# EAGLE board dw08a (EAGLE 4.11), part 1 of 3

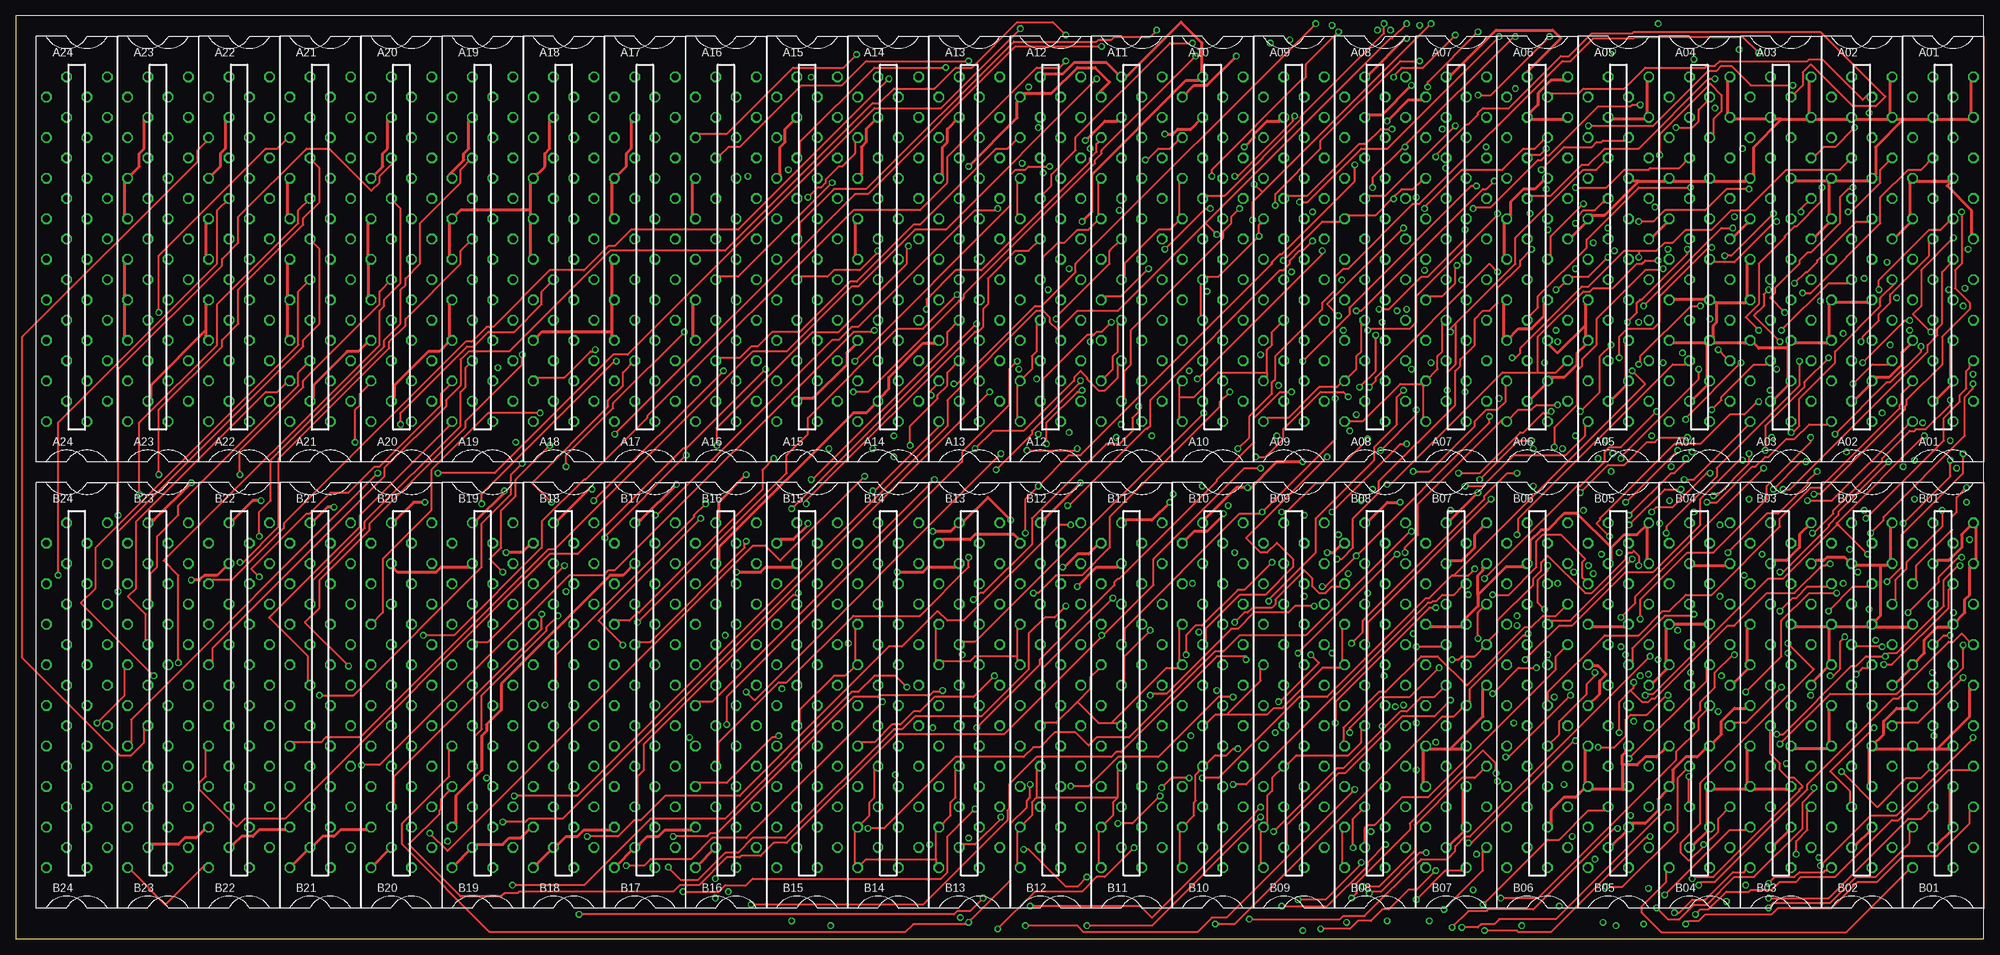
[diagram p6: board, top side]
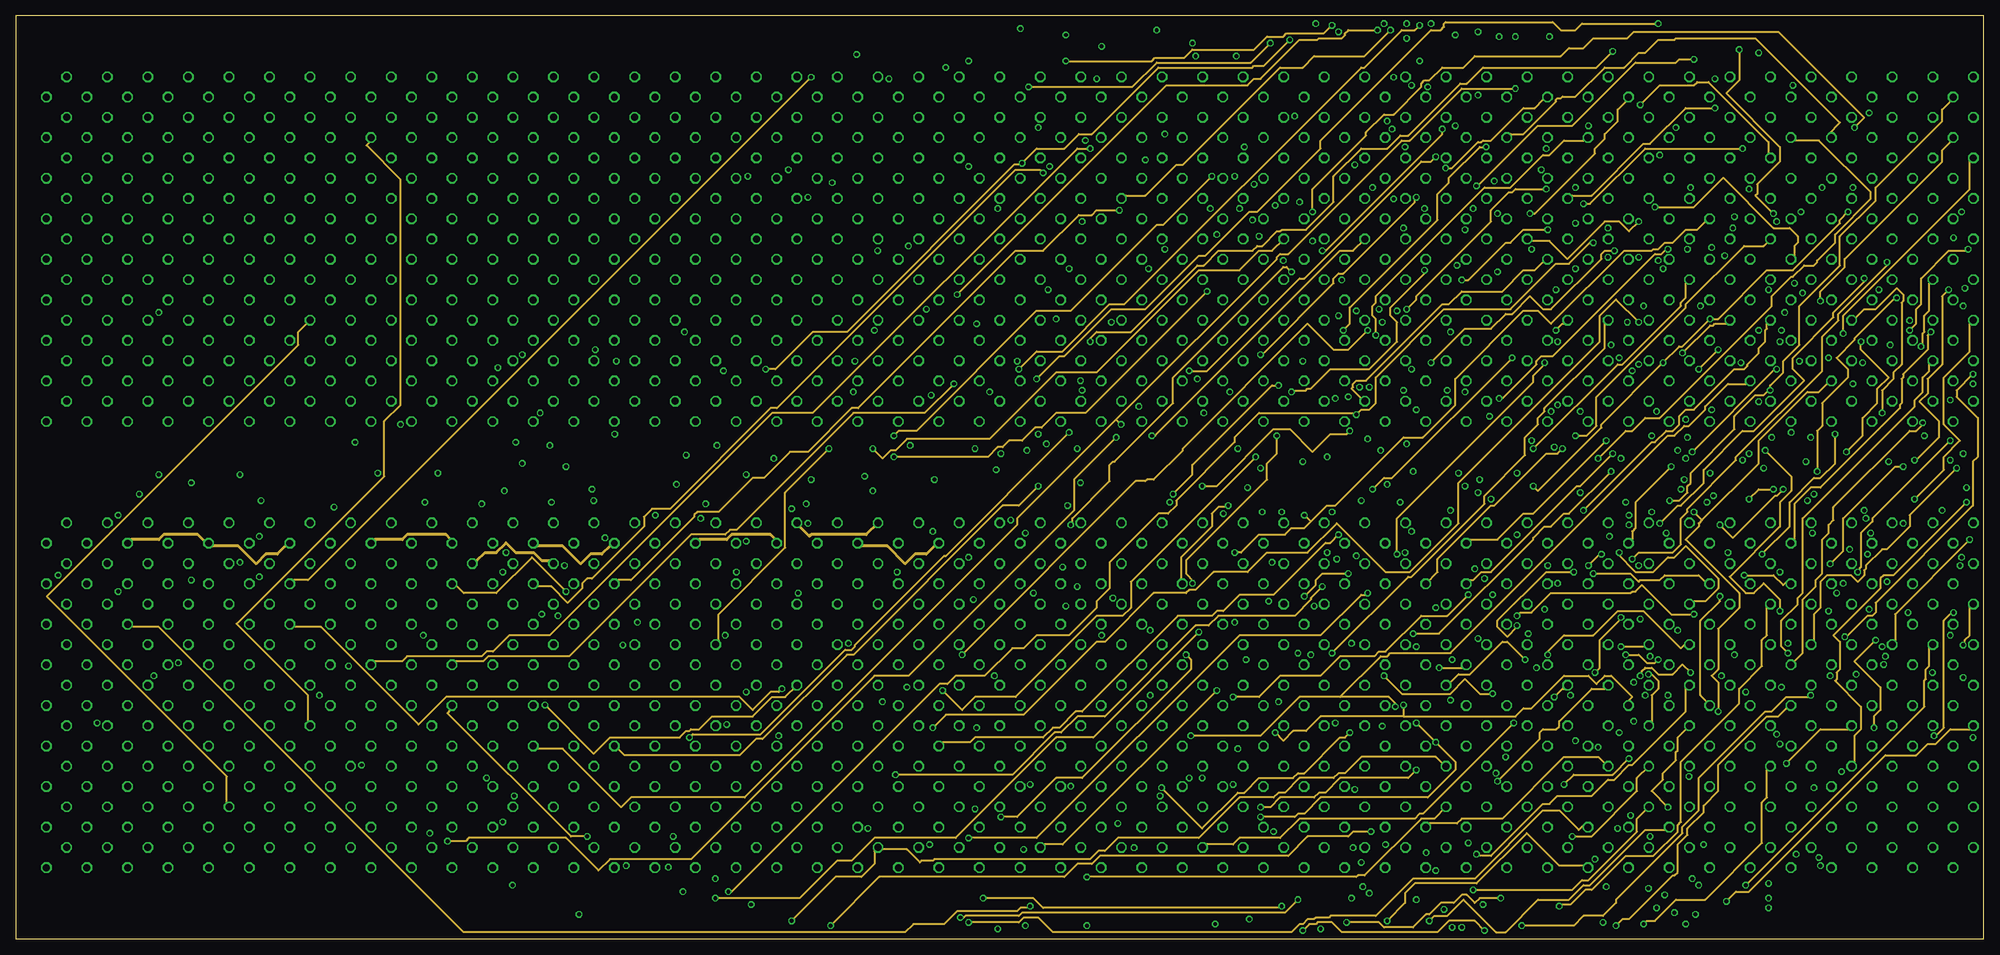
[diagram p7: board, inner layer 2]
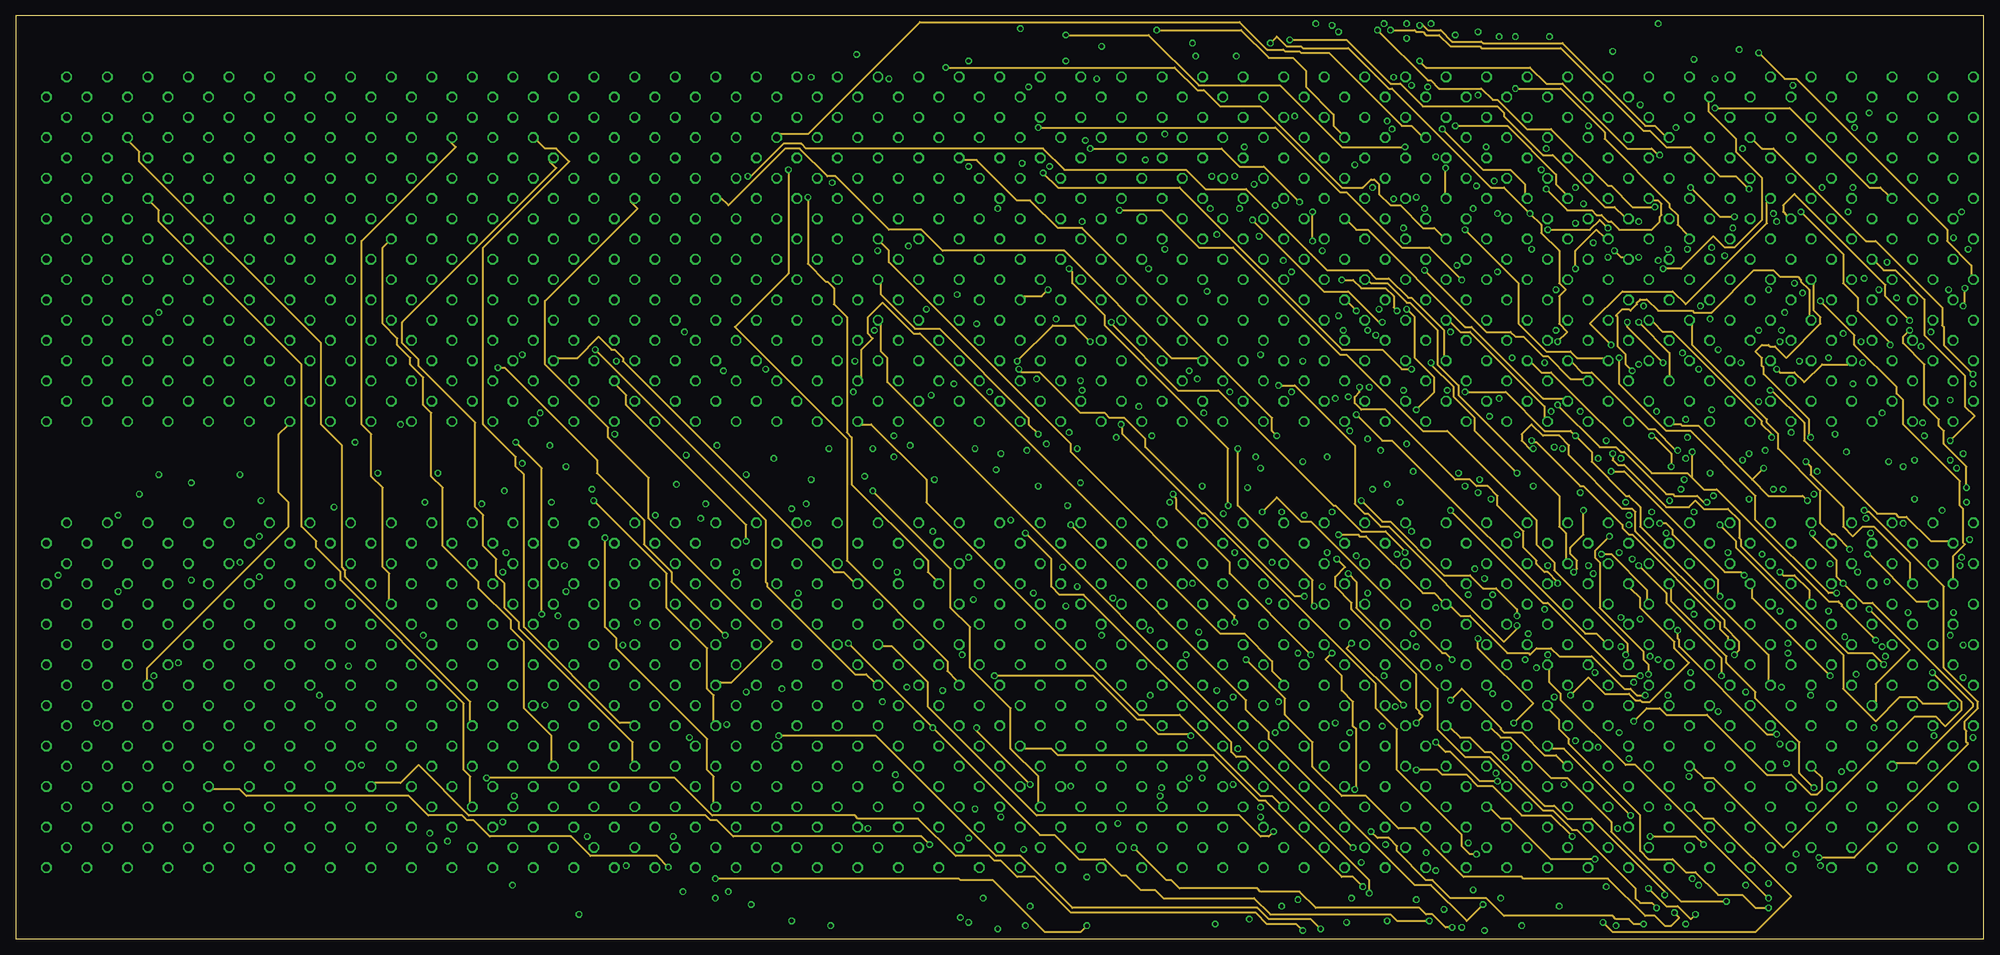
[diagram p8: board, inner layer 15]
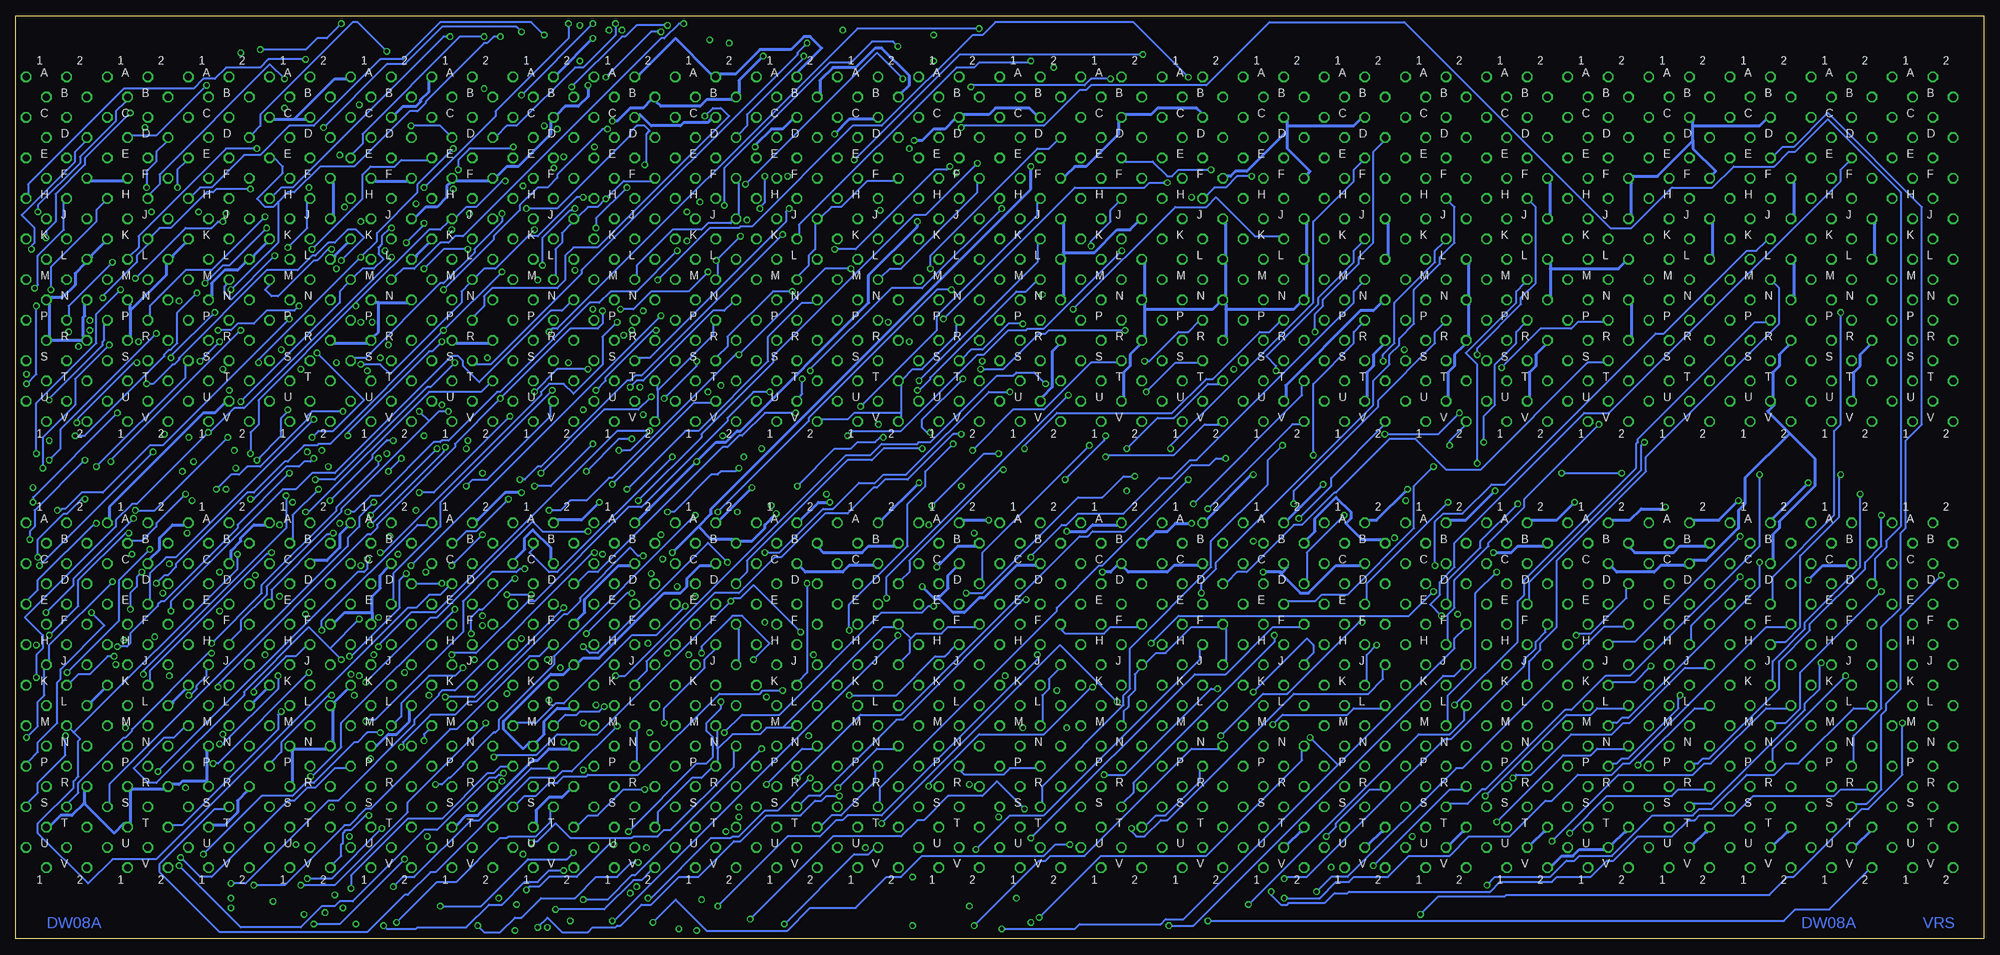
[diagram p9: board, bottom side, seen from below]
Size 307.98 x 144.46 mm. Coordinates in mm from the lower left corner, seen from the top.
Outline: 0,0 307.98,0 307.98,144.46 0,144.46 0,0
Copper layers (1*2*15*16): Top 0.035mm / dielectric 1.5mm / 2 0.035mm / dielectric 0.15mm / 15 0.035mm / dielectric 0.2mm / Bottom 0.035mm
Design rules "10mils": minimum track width 12mil, minimum drill 24mil, track to track 10mil, track to pad 10mil, pad to pad 10mil, via to via 10mil, smd to smd 10mil, copper to edge 25mil, drill to drill 10mil, minimum pad ring 10mil, minimum via ring 8mil, stop-mask expansion 0mil, vias tented up to drill 0mil, thermal gap 10mil
Net classes: 1 supply: width 0.508 mm

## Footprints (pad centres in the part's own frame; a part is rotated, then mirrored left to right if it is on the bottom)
H807 = drill 1.092 octagon: A1 4.763,28.575; A2 -1.587,28.575; B1 1.587,25.4; B2 -4.763,25.4; C1 4.763,22.225; C2 -1.587,22.225; D1 1.587,19.05; D2 -4.763,19.05; E1 4.763,15.875; E2 -1.587,15.875; F1 1.587,12.7; F2 -4.763,12.7; H1 4.763,9.525; H2 -1.587,9.525; J1 1.587,6.35; J2 -4.763,6.35; K1 4.763,3.175; K2 -1.587,3.175; L1 1.587,0; L2 -4.763,0; M1 4.763,-3.175; M2 -1.587,-3.175; N1 1.587,-6.35; N2 -4.763,-6.35; P1 4.763,-9.525; P2 -1.587,-9.525; R1 1.587,-12.7; R2 -4.763,-12.7; S1 4.763,-15.875; S2 -1.587,-15.875; T1 1.587,-19.05; T2 -4.763,-19.05; U1 4.763,-22.225; U2 -1.587,-22.225; V1 1.587,-25.4; V2 -4.763,-25.4

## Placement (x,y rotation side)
A01  M903  [H807]  301.62,106.36 0 top
A02  M903  [H807]  288.93,106.36 0 top
A03  M903  [H807]  276.23,106.36 0 top
A04  M903  [H807]  263.52,106.36 0 top
A05  M903  [H807]  250.82,106.36 0 top
A06  M907  [H807]  238.12,106.36 0 top
A07  M651  [H807]  225.43,106.36 0 top
A08  M651  [H807]  212.72,106.36 0 top
A09  M651  [H807]  200.03,106.36 0 top
A10  M651  [H807]  187.32,106.36 0 top
A11  M651  [H807]  174.62,106.36 0 top
A12  M651  [H807]  161.93,106.36 0 top
A13  W011  [H807]  149.22,106.36 0 top
A14  W011  [H807]  136.53,106.36 0 top
A15  W011  [H807]  123.83,106.36 0 top
A16  W011  [H807]  111.12,106.36 0 top
A17  W011  [H807]  98.42,106.36 0 top
A18  W011  [H807]  85.72,106.36 0 top
A19  W011  [H807]  73.03,106.36 0 top
A20  W011  [H807]  60.33,106.36 0 top
A21  W011  [H807]  47.62,106.36 0 top
A22  W011  [H807]  34.92,106.36 0 top
A23  W011  [H807]  22.23,106.36 0 top
A24  H807  [H807]  9.53,106.36 0 top
B01  M903  [H807]  301.62,36.51 0 top
B02  M903  [H807]  288.93,36.51 0 top
B03  M903  [H807]  276.23,36.51 0 top
B04  M903  [H807]  263.52,36.51 0 top
B05  M903  [H807]  250.82,36.51 0 top
B06  M101  [H807]  238.12,36.51 0 top
B07  M907  [H807]  225.43,36.51 0 top
B08  M651  [H807]  212.72,36.51 0 top
B09  M651  [H807]  200.03,36.51 0 top
B10  M651  [H807]  187.32,36.51 0 top
B11  M651  [H807]  174.62,36.51 0 top
B12  M651  [H807]  161.93,36.51 0 top
B13  M651  [H807]  149.22,36.51 0 top
B14  M651  [H807]  136.53,36.51 0 top
B15  M651  [H807]  123.83,36.51 0 top
B16  M517  [H807]  111.12,36.51 0 top
B17  M517  [H807]  98.42,36.51 0 top
B18  M517  [H807]  85.72,36.51 0 top
B19  M517  [H807]  73.03,36.51 0 top
B20  M517  [H807]  60.33,36.51 0 top
B21  M517  [H807]  47.62,36.51 0 top
B22  M517  [H807]  34.92,36.51 0 top
B23  M517  [H807]  22.23,36.51 0 top
B24  H807  [H807]  9.53,36.51 0 top

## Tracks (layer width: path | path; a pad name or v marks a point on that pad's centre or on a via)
-15V  (via drill 0.61)
  Top 0.508: v76.71,60.45 79.25,60.45 80.26,61.47 B18.B2 | v214.63,128.02 217.93,131.32 219.96,131.32 A07.B2 | A11.B2 169.42,132.33 171.2,134.11 168.91,136.4 166.12,136.4 162.05,132.33 157.73,132.33 A12.B2 156.72,131.06 156.72,128.52 v149.1,120.9 | v191.01,138.18 186.44,133.6 184.4,133.6 A10.B2 | v123.95,65.02 123.95,64.77 121.67,62.48 119.63,62.48 B15.B2 | v205.23,60.45 206.25,60.45 207.26,61.47 B08.B2 | B13.B2 145.03,62.48 149.35,62.48 150.11,63.25 156.21,63.25 156.97,62.48 B12.B2 | v163.83,58.17 164.08,58.17 166.12,60.2 167.89,60.2 169.16,61.47 B11.B2 | v188.98,66.55 188.98,66.29 186.44,63.75 184.4,63.75 B10.B2
  2 0.508: B23.B2 18.03,62.48 22.35,62.48 23.11,63.25 28.45,63.25 29.46,62.23 B22.B2 30.73,61.47 34.8,61.47 37.59,58.67 39.12,60.2 40.89,60.2 42.16,61.47 B21.B2 | B18.B2 81.53,61.47 85.6,61.47 88.39,58.67 89.92,60.2 91.69,60.2 92.96,61.47 B17.B2 | B20.B2 56.13,62.48 60.45,62.48 61.21,63.25 67.31,63.25 68.07,62.48 B19.B2 | B14.B2 132.33,61.47 136.4,61.47 139.19,58.67 140.72,60.2 142.49,60.2 143.76,61.47 B13.B2 | B16.B2 106.93,62.48 111.25,62.48 112.01,63.25 118.11,63.25 118.87,62.48 B15.B2
  Bottom 0.508: B21.B2 43.43,61.47 47.5,61.47 48.51,60.45 54.61,60.45 55.37,61.21 B20.B2 | v76.71,60.45 73.91,60.45 72.9,61.47 68.83,61.47 B19.B2 | B17.B2 94.23,62.48 97.28,62.48 99.82,65.02 99.06,65.79 99.06,66.8 101.35,69.09 104.65,65.79 104.65,63.75 105.92,62.48 B16.B2 | v214.63,128.02 213.87,128.02 211.84,130.05 209.8,130.05 208.53,131.32 A08.B2 207.77,131.06 207.01,130.3 200.91,130.3 199.9,131.32 195.83,131.32 A09.B2 194.82,132.33 194.82,134.37 v191.01,138.18 | A10.B2 182.12,132.33 182.12,134.37 180.09,136.4 176.53,136.4 173.48,139.45 172.47,139.45 168.15,135.13 168.15,133.6 169.42,132.33 A11.B2 | v123.95,65.02 126.49,65.02 127.76,63.75 129.54,63.75 131.06,62.23 B14.B2 | 201.17,64.52 199.14,62.48 195.83,62.48 B09.B2 194.56,62.23 192.79,62.23 190.75,64.26 190.75,64.77 v188.98,66.55 | 201.17,64.52 v205.23,60.45 | B11.B2 170.43,61.47 174.5,61.47 175.51,60.45 181.61,60.45 182.37,61.21 B10.B2 | v163.83,58.17 160.53,61.47 157.73,61.47 B12.B2 | v149.1,120.9 149.1,117.35 199.14,67.31 199.14,66.55 201.17,64.52
A06U1  (via drill 0.61)
  Top 0.305: 215.39,115.82 216.92,117.35 218.69,117.35 219.96,118.62 A07.F2 | 215.39,115.82 212.85,113.28 208.53,113.28 A08.J2 207.26,112.27 204.47,112.27 v198.37,106.17 | 215.39,115.82 v215.65,115.82 | A12.M2 160.78,103.89 160.78,106.68 163.07,108.97 164.08,108.97 166.12,111 167.89,111 169.16,112.27 A11.J2 169.42,113.28 169.42,118.36 A11.F2 | A12.J2 156.72,113.28 156.72,118.36 A12.F2 | A11.M2 173.48,103.89 173.48,105.66 178.82,111 180.59,111 181.86,112.27 A10.J2 182.12,113.28 182.12,118.36 A10.F2 | A10.P2 185.42,97.54 185.42,102.62 A10.M2 186.44,103.63 188.21,103.63 v194.56,109.98 194.56,111.76 194.82,112.01 A09.J2
  15 0.305: A06.U1 242.32,84.58 239.01,84.58 227.84,95.76 226.82,95.76 211.58,111 209.8,111 208.53,112.27 A08.J2 | B06.C1 242.57,59.44 242.57,63.5 241.55,64.52 241.55,69.34 225.81,85.09 225.81,86.61 222.5,89.92 222.5,95.25 218.19,99.57 217.68,99.57 214.63,102.62 212.09,102.62 211.84,102.87 A08.M2
  Bottom 0.305: A07.M2 223.52,103.89 223.52,107.95 222.5,108.97 222.5,110.49 220.98,112.01 A07.J2 219.96,113.03 218.44,114.55 216.92,114.55 v215.65,115.82 212.85,118.62 208.53,118.62 A08.F2 | A12.F2 157.48,118.36 157.48,116.84 169.42,104.9 171.2,104.9 172.47,103.63 A11.M2 | A11.F2 170.43,118.62 174.75,118.62 178.82,114.55 180.34,114.55 181.86,113.03 A10.J2 182.88,112.01 182.88,107.95 183.9,106.93 183.9,105.41 185.42,103.89 A10.M2 | A09.F2 194.82,118.36 194.82,113.28 A09.J2 195.83,112.27 196.09,112.01 199.64,112.01 200.66,111 205.23,111 210.82,105.41 210.82,103.89 A08.M2 | 198.12,106.17 198.12,106.43 v194.56,109.98 | 198.12,106.17 198.12,103.89 A09.M2 | 198.12,106.17 v198.37,106.17
A06V1
  Top 0.305: A12.V2 156.72,81.53 156.72,86.61 A12.T2 159,89.15 159,91.19 159.77,91.95 159.77,96.27 A12.P2 | 182.12,84.84 182.12,86.61 A10.T2 | 182.12,84.84 182.12,81.53 A10.V2 | A11.P2 172.47,96.27 172.47,91.95 171.7,91.19 171.7,89.15 A11.T2 | 195.83,88.65 195.83,92.2 196.6,92.96 196.6,95 A09.P2 | 195.83,88.65 195.83,87.88 A09.T2 | A09.V2 195.83,81.53 199.14,81.53 203.96,86.36 206.76,86.36 207.26,86.87 A08.T2 209.8,89.15 209.8,91.19 210.57,91.95 210.57,96.27 A08.P2 | A07.V2 220.22,81.53 220.22,86.61 A07.T2 | A07.P2 223.27,96.27 223.27,91.95 222.5,91.19 222.5,89.15 A07.T2 | A08.V2 208.53,81.03 210.82,81.03 216.66,86.87 219.96,86.87 A07.T2 | 182.12,84.84 184.4,84.84 188.21,88.65 195.83,88.65
  15 0.305: A06.V1 239.27,81.53 239.27,83.31 227.58,95 226.06,95 224.54,96.52 A07.P2
  Bottom 0.305: 169.42,82.3 169.42,86.61 A11.T2 169.16,87.63 167.64,89.15 166.12,89.15 160.78,94.49 160.78,96.27 A12.P2 | 169.42,82.3 169.42,81.53 A11.V2 | 169.42,82.3 176.78,82.3 177.8,81.28 181.86,81.28 A10.V2 | 207.52,85.85 207.52,86.61 A08.T2 | 207.52,85.85 207.52,81.53 A08.V2 | 207.52,85.85 198.88,94.49 198.88,96.27 A09.P2
B07U1  (via drill 0.61)
  Top 0.305: B15.M2 122.68,34.04 122.68,35.81 128.02,41.15 129.79,41.15 131.06,42.42 B14.J2 131.32,43.43 131.32,48.51 B14.F2 | B13.F2 144.02,48.51 144.02,43.43 B13.J2 145.03,43.43 149.35,43.43 150.11,44.2 156.72,44.2 | B10.F2 182.12,48.51 182.12,43.43 B10.J2 181.86,42.42 180.09,42.42 171.45,33.78 | 156.72,44.2 156.72,48.51 B12.F2 | 156.72,44.2 156.72,43.43 B12.J2 | 166.12,37.08 168.15,39.12 168.15,40.89 169.42,42.16 B11.J2 | 166.12,37.08 162.81,33.78 161.04,33.78 B12.M2 | 171.45,33.78 169.42,33.78 166.12,37.08 | 171.45,33.78 172.47,33.78 B11.M2 | B08.V2 207.52,11.68 207.52,16.76 B08.T2 | v223.52,4.57 229.62,10.67 229.62,13.72 B07.U1 | B08.F2 207.52,48.51 207.52,43.43 B08.J2 207.26,42.42 204.47,42.42 198.12,36.07 196.85,36.07 195.83,35.05 189.48,35.05 | B09.V2 194.82,11.68 194.82,16.76 B09.T2 195.83,18.03 195.83,22.35 196.6,23.11 196.6,25.15 B09.P2 199.14,27.43 200.41,28.7 208.53,28.7 210.57,30.73 210.57,32.77 B08.M2 | 189.48,35.05 194.82,40.39 194.82,42.16 B09.J2 | 189.48,35.05 187.71,35.05 186.44,33.78 B10.M2
  Bottom 0.305: B15.J2 118.62,43.43 118.62,48.51 B15.F2 119.63,48.77 123.95,48.77 128.02,44.7 129.54,44.7 131.06,43.18 B14.J2 132.08,42.16 132.84,41.4 132.84,38.86 133.86,37.85 133.86,36.32 134.62,35.56 134.62,34.04 B14.M2 | B13.M2 147.32,34.04 147.32,38.1 146.3,39.12 146.3,40.64 144.78,42.16 B13.J2 | 167.89,46.99 169.42,48.51 B11.F2 170.43,48.77 172.21,48.77 187.96,33.02 | 167.89,46.99 168.15,46.74 168.15,44.7 169.42,43.43 B11.J2 | 167.89,46.99 167.13,47.75 163.07,47.75 162.05,48.77 157.73,48.77 B12.F2 | B14.F2 132.33,48.77 136.65,48.77 137.67,47.75 143.76,47.75 144.27,48.26 144.02,48.51 B13.F2 | v223.52,4.57 215.9,4.57 211.33,9.14 210.06,9.14 208.53,10.67 B08.V2 | B09.J2 194.82,43.43 194.82,48.51 B09.F2 | B08.P2 210.82,27.69 210.82,32.77 B08.M2 | 198.12,29.72 198.12,32.77 B09.M2 | 198.12,29.72 198.12,27.69 B09.P2 199.14,26.67 200.66,25.15 202.18,25.15 207.52,19.81 207.52,18.03 B08.T2 | 187.96,33.02 190.5,33.02 191.52,32 195.83,32 198.12,29.72 | 187.96,33.02 186.44,33.02 B10.M2
B07V1  (via drill 0.61)
  Top 0.305: 144.02,12.45 144.02,16.76 B13.T2 146.3,19.3 146.3,21.34 147.07,22.1 147.07,26.42 B13.P2 | 144.02,12.45 144.02,11.68 B13.V2 | B14.P2 134.37,26.42 134.37,22.1 133.6,21.34 133.6,19.3 B14.T2 131.32,16.76 131.32,11.68 B14.V2 133.1,12.45 144.02,12.45 | B12.V2 156.72,11.68 156.72,16.76 B12.T2 159,19.3 159,21.34 159.77,22.1 | 159.77,22.1 159.77,26.42 B12.P2 | B11.V2 169.42,11.68 169.42,16.76 B11.T2 171.7,19.3 171.7,21.34 172.47,22.1 | 172.47,22.1 172.47,26.42 B11.P2 | 159.77,22.1 172.47,22.1 | B10.V2 182.12,11.68 182.12,16.76 B10.T2 184.4,19.3 184.4,21.34 184.66,21.59 184.66,25.65 185.17,26.16 185.17,26.42 B10.P2 186.44,27.43 187.71,28.7 189.48,28.7 190.5,29.72 v191.26,29.72 | v219.2,6.1 223.77,10.67 226.31,10.67 B07.V1
  Bottom 0.305: B15.P2 122.68,26.42 122.68,24.64 128.02,19.3 129.54,19.3 131.06,17.78 B14.T2 | v219.2,6.1 215.39,6.1 211.58,9.91 211.07,9.91 v191.26,29.72 | B11.P2 173.48,26.42 173.48,24.64 178.82,19.3 180.34,19.3 181.86,17.78 B10.T2 | B13.P2 148.34,26.67 152.4,26.67 153.42,25.65 159.51,25.65 160.02,26.16 159.77,26.42 B12.P2
GND  (via drill 0.61)
  Top 0.508: B20.U2 B20.V2 | B21.V2 B21.U2 46.74,14.73 48.01,16 49.78,16 50.8,17.02 54.86,17.02 B20.T2 | B23.U2 21.34,14.73 25.4,14.73 26.42,15.75 28.19,15.75 29.46,17.02 B22.T2 | B21.T2 42.16,17.02 38.1,17.02 37.08,16 35.31,16 34.04,14.73 B22.U2 | B16.U2 B16.V2 | B17.V2 B17.U2 97.54,14.73 98.81,16 100.58,16 101.6,17.02 105.66,17.02 B16.T2 | B19.V2 B19.U2 72.14,14.73 76.2,14.73 77.22,15.75 78.99,15.75 80.26,17.02 B18.T2 | B18.V2 B18.U2 84.84,14.73 86.11,16 87.88,16 88.9,17.02 92.96,17.02 B17.T2 | v166.12,55.12 169.16,58.17 172.47,58.17 B11.C2 | v112.78,57.4 116.59,57.4 117.35,58.17 121.67,58.17 B15.C2 | A15.U2 122.94,84.58 124.71,84.58 130.05,89.92 130.05,91.69 131.32,92.96 A14.R2 | A14.J2 131.32,112.01 131.32,106.93 A14.L2 | A13.R2 143.76,93.22 141.99,93.22 136.65,87.88 136.65,86.11 135.38,84.84 A14.U2 133.1,82.3 131.06,82.3 109.98,61.21 109.98,59.44 B16.C2 | v137.92,57.4 141.99,57.4 142.75,58.17 147.07,58.17 B13.C2 | B19.T2 68.83,18.03 68.83,22.35 72.9,26.42 72.9,31.75 73.66,32.51 73.66,33.53 75.95,35.81 75.95,39.88 92.96,56.9 95,56.9 B17.C2 | B07.U2 224.54,14.73 226.57,16.76 B07.T1 226.57,18.03 226.57,23.11 B07.R1 | B07.R2 220.22,24.38 220.22,29.46 B07.N2 221.23,29.72 224.54,29.72 | 224.54,29.72 226.31,29.72 B07.N1 | 224.54,29.72 229.62,34.8 229.62,39.12 B07.K1 | B06.T1 240.28,18.03 240.28,20.07 242.32,22.1 244.09,22.1 245.36,23.37 B05.R2 | 251.46,23.37 246.63,23.37 B05.R2 | 251.46,23.37 251.71,23.37 B05.R1 | B05.N2 245.62,29.46 245.62,24.38 B05.R2 | 251.46,27.18 251.46,23.37 | 251.46,27.18 251.46,28.7 251.97,29.21 251.97,29.46 B05.N1 | B05.J2 246.63,42.67 247.65,42.67 248.92,41.4 247.9,40.39 247.9,38.35 B05.L2
  Top 0.508: B01.C2 300.74,59.18 302.51,59.18 304.55,61.21 304.55,63.25 B01.A1 306.83,64.52 306.83,59.44 B01.C1 305.82,58.17 305.82,53.85 305.05,53.09 305.05,51.05 B01.F1 302.51,48.77 300.74,48.77 298.7,46.74 298.7,44.7 B01.J2 296.42,42.16 294.39,40.13 B02.K1 | B01.U2 300.74,14.73 302.77,16.76 B01.T1 302.77,18.03 302.77,23.11 B01.R1 | B02.U2 288.04,14.73 290.07,16.76 B02.T1 | B02.N1 290.07,29.46 290.07,24.38 B02.R1 | B02.N1 291.08,29.72 296.16,29.72 B01.N2 297.43,29.72 300.74,29.72 | 300.74,29.72 302.51,29.72 B01.N1 | 300.74,29.72 305.82,34.8 305.82,39.12 B01.K1 | B01.L2 296.16,36.07 294.39,36.07 292.35,34.04 292.35,32 B02.N1 | B03.C2 275.34,59.18 277.11,59.18 279.15,61.21 279.15,63.25 B03.A1 | B03.C1 281.69,59.18 282.96,59.18 283.46,59.69 286.26,59.69 286.77,59.18 B02.C2 288.04,58.42 291.85,58.42 | 291.85,58.42 293.12,58.42 B02.C1 293.37,59.44 293.37,64.52 B02.A1 | B03.F1 278.38,48.77 283.46,48.77 B02.F2 | B02.F1 289.81,48.77 284.73,48.77 B02.F2 | B01.F2 296.16,48.77 291.08,48.77 B02.F1 | B03.K1 281.43,40.39 283.46,42.42 B02.J2 283.72,43.43 283.72,48.51 B02.F2 | B03.U2 275.34,14.73 277.37,16.76 B03.T1 | B04.U2 262.64,14.73 264.67,16.76 B04.T1 264.67,18.03 264.67,23.11 B04.R1 265.68,23.37 270.76,23.37 B03.R2 | B03.N2 271.02,29.46 271.02,24.38 B03.R2 | B03.R1 277.11,23.37 272.03,23.37 B03.R2 | B03.N1 278.38,29.72 283.46,29.72 B02.N2 283.72,30.73 283.72,35.81 B02.L2 | 291.85,58.42 291.85,50.55 B02.F1 | B07.C2 224.54,59.18 226.31,59.18 228.35,61.21 228.35,63.25 B07.A1 | B07.F2 221.23,48.77 226.31,48.77 B07.F1 226.57,49.78 228.85,52.07 228.85,53.85 | 228.85,53.85 228.85,56.9 229.62,57.66 229.62,58.17 B07.C1
  Top 0.508: 228.85,53.85 233.17,58.17 235.97,58.17 B06.C2 236.98,59.44 236.98,62.23 238.76,64.01 239.78,64.01 242.32,66.55 244.35,66.55 249.68,61.21 | B04.C2 262.64,58.42 267.72,58.42 B04.C1 | B05.F2 246.63,48.77 251.71,48.77 B05.F1 | 249.68,61.21 249.68,59.44 B05.C2 | 249.68,61.21 251.71,63.25 253.75,63.25 B05.A1 255.27,64.52 255.27,59.44 B05.C1 | B05.K1 256.29,40.13 258.32,42.16 B04.J2 258.32,43.43 258.32,48.51 B04.F2 259.33,49.28 264.41,49.28 B04.F1 | B04.K1 268.99,40.13 271.02,42.16 B03.J2 271.02,43.43 271.02,48.51 B03.F2 | B05.U2 249.94,14.73 251.97,16.76 B05.T1 252.98,18.03 255.02,18.03 257.05,20.07 257.05,21.84 258.32,23.11 B04.R2 259.33,24.38 259.33,26.42 261.37,28.45 263.14,28.45 264.41,29.72 B04.N1 266.95,32 266.95,34.04 268.99,36.07 270.76,36.07 B03.L2 | 251.46,27.18 253.75,27.18 255.02,28.45 256.79,28.45 258.06,29.72 B04.N2 | A01.U2 300.74,84.58 302.77,86.61 A01.T1 302.77,87.88 302.77,92.96 A01.R1 | A02.U2 288.04,84.58 290.07,86.61 A02.T1 291.08,87.88 293.12,87.88 295.15,89.92 295.15,91.69 296.42,92.96 A01.R2 | A03.K1 281.69,109.98 283.72,112.01 A02.J2 283.72,113.28 283.72,118.36 A02.F2 | A03.F1 278.38,118.62 283.46,118.62 A02.F2 | A02.F2 284.73,118.62 289.81,118.62 A02.F1 291.08,119.63 291.08,123.95 295.4,128.27 | A02.K1 294.39,109.98 296.42,112.01 A01.J2 296.42,113.28 296.42,118.36 A01.F2 297.43,118.62 302.51,118.62 A01.F1 302.77,118.36 302.26,117.86 306.07,114.05 306.07,110.24 A01.K1 | A06.N2 232.92,99.31 232.92,94.23 A06.R2 235.2,95.5 237.24,95.5 239.27,97.54 239.27,99.31 A06.N1 | A06.U2 237.24,84.58 239.27,86.61 A06.T1 240.28,87.88 242.32,87.88 244.35,89.92 244.35,91.69 245.62,92.96 A05.R2 245.62,94.23 245.62,96.01
  Top 0.508: 245.62,96.01 245.62,99.31 A05.N2 | 245.62,96.01 241.3,91.69 240.03,92.96 A06.R1 | A03.U2 275.34,84.58 277.37,86.61 A03.T1 277.37,87.88 277.37,92.46 | 277.37,92.46 277.37,92.96 A03.R1 278.38,93.22 283.46,93.22 A02.R2 283.72,94.23 283.72,99.31 A02.N2 284.73,99.57 289.81,99.57 A02.N1 | A05.U2 249.94,84.58 251.97,86.61 A05.T1 251.97,87.88 251.97,92.96 A05.R1 | A04.U2 262.64,84.58 264.67,86.61 A04.T1 264.67,87.88 264.67,92.96 A04.R1 | A04.R1 265.68,93.22 270.76,93.22 A03.R2 272.03,93.22 272.8,92.46 277.37,92.46 | A04.R2 259.33,93.22 264.41,93.22 A04.R1 | A04.N2 259.33,100.08 264.41,100.08 A04.N1 265.68,99.57 266.19,99.57 | 266.19,99.57 270.76,99.57 A03.N2 271.02,100.58 271.02,105.66 A03.L2 | A04.K1 268.99,109.98 271.02,112.01 A03.J2 | 266.19,99.57 266.19,96.52 265.68,96.01 265.68,94.23 A04.R1 | A06.L2 232.92,106.93 232.92,112.01 A06.J2 233.93,113.28 233.93,115.32 235.97,117.35 237.74,117.35 239.01,118.62 A06.F1 | v218.44,133.6 213.87,129.03 211.84,129.03 A08.C2 | A06.K1 243.59,109.98 245.62,112.01 A05.J2 246.63,113.28 248.67,113.28 254,118.62 | A05.K1 256.29,109.98 258.32,112.01 A04.J2 | 254,118.62 258.06,118.62 A04.F2 259.33,118.62 264.41,118.62 A04.F1 265.68,118.62 270.76,118.62 A03.F2 272.03,119.63 272.03,123.95 276.35,128.27 | 254,118.62 252.98,118.62 A05.F1 | A06.C1 242.32,128.27 237.24,128.27 A06.C2 236.98,129.29 238.25,130.56 238.25,132.33 240.28,134.37 242.32,134.37 A06.A1 | A05.C2 249.94,128.27 255.02,128.27 A05.C1 255.27,129.29 255.27,134.37 A05.A1 | 276.35,128.27 275.34,128.27 A03.C2 274.07,128.27 268.99,128.27 A04.C1 267.97,129.29 267.97,134.37 A04.A1
  Top 0.508: 276.35,128.27 280.42,128.27 A03.C1 | A03.A1 280.67,134.37 280.67,129.29 A03.C1 | A03.C1 281.69,128.27 286.77,128.27 A02.C2 288.04,128.27 293.12,128.27 A02.C1 | A02.A1 293.37,134.37 293.37,129.29 A02.C1 | 295.4,128.27 294.39,128.27 A02.C1 | 295.4,128.27 299.47,128.27 A01.C2 300.74,128.27 305.82,128.27 A01.C1 306.07,129.29 306.07,134.37 A01.A1 | v179.83,125.98 181.1,125.98 181.86,126.75 183.9,126.75 A10.C2 | A14.F2 132.33,119.63 132.33,123.95 133.1,124.71 133.1,126.75 A14.C2 | A13.F2 145.03,119.63 145.03,123.95 145.8,124.71 145.8,126.75 A13.C2 | v167.39,124.97 170.43,128.02 172.47,128.02 A11.C2 | A15.F2 119.63,119.63 119.63,123.95 120.4,124.71 120.4,126.75 A15.C2 | A16.R2 105.92,94.23 105.92,99.31 A16.N2 | A16.F2 105.92,118.36 105.92,113.28 A16.J2 | 93.22,95 93.22,99.31 A17.N2 93.22,100.58 93.22,105.66 A17.L2 | 93.22,95 93.22,94.23 A17.R2 | A17.J2 93.22,113.28 93.22,118.36 A17.F2 95.5,120.9 95.5,122.94 96.27,123.7 96.27,128.02 A17.C2 | A18.L2 80.52,106.93 80.52,112.01 A18.J2 80.52,113.28 80.52,114.05 | 80.52,114.05 80.52,118.36 A18.F2 82.8,120.9 82.8,122.94 83.57,123.7 83.57,128.02 A18.C2 | A20.U2 59.18,84.84 59.18,86.61 64.52,91.95 66.29,91.95 67.56,93.22 A19.R2 67.82,94.23 67.82,99.31 A19.N2 | A19.L2 67.82,106.93 67.82,112.01 A19.J2 69.6,114.05 80.52,114.05 | A19.C2 70.87,128.02 70.87,123.7 70.1,122.94 70.1,121.92 67.82,119.63 A19.F2 | A21.U2 46.48,84.84 46.48,86.61 51.82,91.95 53.59,91.95 54.86,93.22 A20.R2 | A20.N2 55.12,100.58 55.12,105.66 A20.L2 55.12,106.93 55.12,112.01 A20.J2 | A20.C2 58.17,128.02 58.17,123.7 57.4,122.94 57.4,120.9 A20.F2
  Top 0.508: A23.R2 17.02,94.23 17.02,99.31 A23.N2 17.02,100.58 17.02,105.66 A23.L2 | A23.J2 17.02,113.28 17.02,118.36 A23.F2 19.3,120.9 19.3,122.94 20.07,123.7 20.07,128.02 A23.C2 | B19.C2 70.87,58.17 66.55,58.17 65.79,57.4 59.69,57.4 58.93,58.17 B20.C2 | A21.R2 42.42,94.23 42.42,99.31 A21.N2 42.42,100.58 42.42,105.66 A21.L2 | A21.F2 42.42,118.36 42.42,113.28 A21.J2 | v27.43,56.13 28.7,56.13 29.46,56.9 31.5,56.9 B22.C2 | 29.72,95.25 29.72,99.31 A22.N2 | 29.72,95.25 29.72,94.23 A22.R2 | A22.J2 29.72,112.01 29.72,106.93 A22.L2 | A22.C2 32.77,128.02 32.77,123.7 32,122.94 32,120.9 A22.F2 | 29.72,95.25 21.08,86.61 21.08,84.84 A23.U2 | 93.22,95 82.3,95 A18.R2 | v192.28,123.95 193.8,125.48 193.8,125.98 195.83,128.02 197.87,128.02 A09.C2
  2 0.508: B18.C2 83.57,59.18 82.3,59.18 81.03,60.45 78.23,60.45 76.71,61.98 75.18,60.45 73.41,60.45 72.14,59.18 B19.C2
  Bottom 0.508: B20.T2 55.88,16.76 56.13,16.76 58.17,14.73 B20.U2 59.44,13.97 63.25,13.97 64.26,12.95 66.04,12.95 67.56,11.43 B19.V2 | B21.T2 43.18,16.76 43.43,16.76 45.47,14.73 B21.U2 | B23.U2 20.07,14.73 19.81,14.73 17.78,16.76 B23.T2 | B22.T2 30.48,16.76 30.73,16.76 32.77,14.73 B22.U2 | B16.T2 106.68,16.76 106.93,16.76 108.97,14.73 B16.U2 | B17.T2 93.98,16.76 94.23,16.76 96.27,14.73 B17.U2 | B19.T2 68.58,16.76 68.83,16.76 70.87,14.73 B19.U2 | B18.T2 81.28,16.76 81.53,16.76 83.57,14.73 B18.U2 | B11.C2 173.74,58.42 177.55,58.42 178.56,57.4 184.4,57.4 B10.C2 | 163.45,53.47 162.05,54.86 162.05,56.9 160.78,58.17 B12.C2 | 163.45,53.47 163.58,53.34 161.29,51.05 159.51,51.05 157.23,53.34 156.46,53.34 151.38,58.42 148.34,58.42 B13.C2 | v166.12,55.12 164.08,53.09 163.58,53.59 163.45,53.47 | B15.C2 122.94,58.42 126.75,58.42 127.76,57.4 133.86,57.4 134.62,58.17 B14.C2 135.64,58.42 136.65,57.4 v137.92,57.4 | 109.86,57.28 108.97,58.17 B16.C2 | 109.86,57.28 109.98,57.15 106.93,54.1 105.66,54.1 101.35,58.42 97.54,58.42 B17.C2 | v112.78,57.4 109.98,57.4 109.86,57.28 | A13.N2 144.02,100.58 144.02,105.66 A13.L2 144.02,106.93 144.02,107.44 | 144.02,107.44 144.02,112.01 A13.J2 | A13.U2 147.32,84.84 145.8,86.36 145.8,91.95 144.78,92.96 A13.R2 | 131.32,98.55 131.32,94.23 A14.R2 132.08,92.96 133.6,91.44 133.6,89.66 134.62,88.65 134.62,84.84 A14.U2 | 131.32,98.55 131.32,99.31 A14.N2 131.32,100.58 131.32,105.66 A14.L2 | 144.02,107.44 139.19,107.44 135.64,111 133.6,111 132.33,112.27 A14.J2 | B09.C2 199.14,58.42 200.91,58.42 202.95,56.39 202.95,55.12 203.96,54.1 206.5,54.1 216.66,43.94 219.2,43.94 219.96,43.18 B07.J2 221.23,42.42 222.25,41.4 224.28,41.4 231.65,34.04 231.65,32.77 228.6,29.72 227.58,30.73 B07.N1 226.57,30.73 225.3,32 225.3,34.04 223.27,36.07 221.23,36.07 B07.L2
  Bottom 0.508: B07.T1 226.57,18.03 226.57,20.07 224.54,22.1 222.5,22.1 221.23,23.37 B07.R2 | B05.L2 246.38,35.81 246.38,34.04 248.41,32 249.68,32 251.71,29.97 B05.N1 | B07.N2 221.23,29.72 224.54,29.72 226.31,27.94 227.08,27.94 235.71,19.3 237.49,19.3 239.01,17.78 B06.T1 | B01.L2 296.16,36.83 296.16,37.08 294.13,39.12 B02.K1 | 297.31,21.21 299.21,19.3 300.99,19.3 302.51,17.78 B01.T1 | 297.31,21.21 297.18,21.34 297.18,23.11 B01.R2 | 297.31,21.21 292.61,16.51 291.08,18.03 B02.T1 290.07,18.03 290.07,23.11 B02.R1 289.81,23.37 284.73,23.37 B02.R2 283.46,24.13 282.45,24.13 281.94,24.64 278.13,24.64 | B04.A1 268.99,64.77 270.76,64.77 272.8,62.74 272.8,62.23 274.32,60.71 274.32,59.44 B03.C2 | B03.A1 281.69,64.77 283.46,64.77 285.5,62.74 285.5,60.96 287.02,59.44 B02.C2 | B02.L2 283.46,36.83 283.46,37.08 281.43,39.12 B03.K1 | 278.13,24.64 278.13,24.38 B03.R1 | 278.13,24.64 278.13,29.46 B03.N1 | B03.T1 277.11,17.78 275.34,17.78 273.3,19.81 273.3,21.59 271.78,23.11 B03.R2 | B08.C2 211.84,58.42 213.61,58.42 218.95,53.09 218.95,51.05 220.22,49.78 B07.F2 | B07.C2 224.28,59.44 224.28,61.21 227.08,64.01 228.35,62.74 228.35,60.96 229.87,59.44 B07.C1 | 252.22,51.05 252.22,53.59 250.95,54.86 250.95,56.9 249.68,58.17 B05.C2 | 252.22,51.05 252.22,49.78 B05.F1 | B04.C2 261.37,59.18 259.33,59.18 257.3,61.21 257.3,63.25 256.03,64.52 B05.A1 | B05.K1 256.03,39.12 258.06,37.08 258.06,36.83 B04.L2 258.32,35.81 258.32,30.73 B04.N2 259.33,29.72 264.41,29.72 B04.N1 264.67,29.46 264.67,24.38 B04.R1 | B03.L2 270.76,36.83 270.76,37.08 268.73,39.12 B04.K1 | 252.22,51.05 256.54,51.05 258.06,49.53 B04.F2
  Bottom 0.508: A01.N2 297.18,99.31 297.18,97.54 297.43,97.28 297.43,94.23 A01.R2 297.43,93.73 302.51,93.73 A01.R1 302.77,94.23 302.77,99.31 A01.N1 302.51,100.33 300.74,100.33 298.7,102.36 298.7,104.14 297.18,105.66 A01.L2 296.16,106.68 296.16,106.93 294.13,108.97 A02.K1 | A03.K1 281.43,108.97 283.46,106.93 283.46,106.68 A02.L2 284.48,105.66 284.48,103.89 290.07,98.3 | A02.F1 291.08,118.62 296.16,118.62 A01.F2 | A06.R2 233.93,93.22 239.01,93.22 A06.R1 | 251.21,99.57 246.63,99.57 A05.N2 | 251.21,99.57 251.71,99.57 A05.N1 | 290.07,98.3 290.07,99.31 A02.N1 | 290.07,98.3 290.07,94.23 A02.R1 | A04.R2 258.06,93.22 252.98,93.22 A05.R1 251.97,94.23 251.21,95 251.21,99.57 | A04.K1 268.73,108.97 270.76,106.93 270.76,106.68 A03.L2 272.03,105.92 273.3,104.65 275.34,104.65 277.37,102.62 277.37,100.58 A03.N1 | A09.C2 199.14,128.27 199.64,127.76 203.45,127.76 203.96,127.25 208.53,127.25 210.31,129.03 210.57,128.78 A08.C2 | v218.44,133.6 218.44,131.83 219.96,130.3 222,130.3 223.27,129.03 A07.C2 224.28,128.02 224.28,125.98 229.36,120.9 231.14,120.9 232.66,119.38 A06.F2 233.93,118.62 239.01,118.62 A06.F1 240.03,118.36 240.54,117.86 240.54,116.08 242.06,114.55 243.84,114.55 245.36,113.03 A05.J2 | A05.L2 245.36,106.68 245.36,106.93 243.33,108.97 A06.K1 | A05.F2 246.63,118.62 251.71,118.62 A05.F1 | A04.L2 258.06,106.68 258.06,106.93 256.03,108.97 A05.K1 | A04.F2 258.32,118.36 258.32,113.28 A04.J2 | A06.A1 243.33,134.37 243.33,132.59 244.6,131.32 244.6,131.06 245.36,130.3 247.4,130.3 248.67,129.03 A05.C2 | 264.41,128.27 267.72,128.27 A04.C1 | 264.41,128.27 262.64,128.27 A04.C2
  Bottom 0.508: 264.41,128.27 258.06,134.62 256.29,134.62 A05.A1 | B02.A1 293.37,65.79 293.37,67.56 278.64,82.3 276.86,82.3 275.34,83.82 A03.U2 | v179.83,125.98 177.55,128.27 173.74,128.27 A11.C2 | A13.C2 148.34,129.03 149.35,130.05 154.69,130.05 155.7,129.03 159.77,129.03 A12.C2 161.04,128.27 162.56,126.75 164.34,126.75 166.12,124.97 v167.39,124.97 | A13.F2 143.76,119.38 142.24,120.9 140.46,120.9 135.38,125.98 135.38,128.02 A14.C2 134.37,129.03 130.3,129.03 129.29,130.05 123.19,130.05 122.43,129.29 A15.C2 | 118.62,98.55 118.62,99.31 A15.N2 | 118.62,98.55 118.62,94.23 A15.R2 | A15.N2 118.62,100.58 118.62,105.66 A15.L2 118.62,106.93 118.62,112.01 A15.J2 | A16.J2 105.92,112.01 105.92,106.93 A16.L2 105.92,105.66 105.92,100.58 A16.N2 106.93,99.57 107.95,98.55 118.62,98.55 | 108.97,126.49 108.97,123.7 105.41,120.14 105.92,119.63 A16.F2 | 108.97,126.49 108.97,127.25 | 108.97,127.25 108.97,128.02 A16.C2 | 108.97,126.49 115.32,120.14 117.09,120.14 117.86,119.38 118.36,119.38 A15.F2 | A17.U2 96.52,84.84 96.52,88.65 95.5,89.66 95.5,91.44 93.98,92.96 A17.R2 | A17.J2 93.22,112.01 93.22,106.93 A17.L2 | A16.U2 109.22,84.84 109.22,86.61 97.54,98.3 95.5,98.3 94.23,99.57 A17.N2 | 108.97,127.25 98.55,127.25 97.54,128.27 A17.C2 | A18.U2 83.82,84.84 83.82,88.65 82.8,89.66 82.8,91.44 81.28,92.96 A18.R2 80.52,94.23 80.52,99.31 A18.N2 80.52,100.58 80.52,105.66 A18.L2 | A19.U2 71.12,84.84 71.12,88.65 70.1,89.66 70.1,91.44 68.58,92.96 A19.R2 | 67.82,104.9 67.82,100.58 A19.N2 | 67.82,104.9 67.82,105.66 A19.L2 | A19.F2 67.82,118.36 67.82,113.28 A19.J2 | A20.N2 55.12,99.31 55.12,94.23 A20.R2
  Bottom 0.508: A20.J2 55.12,113.28 55.12,118.36 A20.F2 54.86,119.38 51.05,119.38 45.47,124.97 | A23.U2 20.32,84.84 20.32,88.65 19.3,89.66 19.3,91.44 17.78,92.96 A23.R2 | A23.J2 17.02,112.01 17.02,106.93 A23.L2 | B20.C2 57.4,57.4 51.56,57.4 50.55,58.42 46.74,58.42 B21.C2 45.47,59.18 43.43,59.18 38.35,64.26 38.35,67.06 37.34,68.07 37.34,72.14 30.35,79.12 | A21.J2 42.42,112.01 42.42,106.93 A21.L2 | 45.47,124.97 45.47,123.7 41.91,120.14 42.42,119.63 A21.F2 | 45.47,124.97 45.47,127.25 | 45.47,127.25 45.47,128.02 A21.C2 | v27.43,56.13 25.15,58.42 21.34,58.42 B23.C2 | A22.R2 30.48,92.96 32,91.44 32,89.66 33.02,88.65 33.02,84.84 A22.U2 32.77,83.57 33.78,82.55 30.35,79.12 | A22.L2 29.72,105.66 29.72,100.58 A22.N2 | A22.F2 29.72,118.36 29.72,113.28 A22.J2 | 30.35,79.12 26.42,75.18 26.42,70.87 32,65.28 32,64.26 33.02,63.25 33.02,59.44 B22.C2 | 45.47,127.25 35.05,127.25 34.04,128.27 A22.C2 | 67.82,104.9 57.15,104.9 56.13,105.92 A20.L2 | v192.28,123.95 192.28,124.21 189.74,126.75 187.96,126.75 186.44,128.27 A10.C2 | 131.32,98.55 120.65,98.55 119.63,99.57 A15.N2
N$1  (via drill 0.61)
  Top 0.305: v230.89,68.83 211.58,49.53 211.58,46.74 B08.H2
  Bottom 0.305: v230.89,68.83 235.97,63.75 237.49,63.75 239.01,62.23 B06.B1
N$2
  Top 0.305: B08.N2 207.77,30.73 207.77,33.02 213.36,38.61 214.38,38.61 219.96,44.2 222.5,44.2 227.08,39.62 236.22,48.77 237.24,48.77 239.01,50.55 241.05,50.55 B06.E1
N$3
  Top 0.305: B08.U2 211.07,14.99 211.07,17.27 211.58,17.78 212.6,17.78 216.92,22.1 220.98,22.1 241.05,42.16 241.05,44.2 B06.H1
N$4  (via drill 0.61)
  Top 0.305: v222.25,51.82 221.23,51.82 206.5,37.08 v206.5,33.78
  2 0.305: v240.79,37.85 242.06,39.12 242.32,39.12 B06.K1
  Bottom 0.305: v240.79,37.85 236.22,37.85 v222.25,51.82 | v206.5,33.78 206.5,36.07 200.15,42.42 200.15,43.69 198.37,45.47 B09.H2
N$5  (via drill 0.61)
  Top 0.305: v227.33,14.99 227.84,14.99 243.84,30.99 v244.09,30.99
  Bottom 0.305: v227.33,14.99 227.08,15.24 226.31,15.24 223.52,18.03 221.23,15.75 211.58,15.75 211.33,16 207.52,16 206.5,17.02 205.49,17.02 195.58,26.92 195.58,29.46 B09.N2 | v244.09,30.99 244.09,32 243.33,32.77 B06.M1
N$6  (via drill 0.61)
  Top 0.305: v224.54,37.34 222,34.8 216.92,34.8 208.03,25.91 207.01,25.91 198.88,17.78 198.88,14.99 B09.U2
  15 0.305: v224.54,37.34 226.31,39.12 232.41,33.02 232.41,32.77 232.92,32.26 235.71,32.26 239.27,28.7 241.05,28.7 242.32,27.43 B06.P1
N_3CYCLE  (via drill 0.61)
  Top 0.305: v85.85,58.42 73.91,46.48 72.14,46.48 B19.H2
  Bottom 0.305: v85.85,58.42 85.85,65.28 84.58,66.55 81.53,66.55 76.96,71.12 74.93,71.12 51.31,94.74 50.04,94.74 37.08,107.7 35.56,107.7 34.04,109.22 A22.K2
N_AC00  (via drill 0.61)
  Top 0.305: v86.11,73.91 86.11,75.69 93.47,83.06 93.47,83.82 v104.65,95
  Bottom 0.305: v86.11,73.91 89.15,70.87 89.15,64.26 99.57,53.85 103.63,53.85 104.65,52.83 108.97,52.83 B16.E2 | v104.65,95 104.65,97.79 103.38,99.06 103.38,100.08 97.79,105.66 97.79,106.68 95.5,108.97 95.5,123.19 93.98,124.71 A17.D2
N_AC01  (via drill 0.61)
  2 0.305: v127.25,76.71 120.4,69.85 120.4,61.21 109.98,50.8 109.98,46.74 B16.H2
  Bottom 0.305: v127.25,76.71 127.25,77.22 104.9,99.57 104.9,112.27 98.55,118.62 98.55,120.4 97.28,121.67 A17.E2
N_AC02
  15 0.305: B16.K2 110.24,40.13 112.01,40.13 118.36,46.48 99.06,65.79 99.06,72.14 92.71,78.49 92.71,80.01 82.8,89.92 82.8,99.82 97.28,114.3 96.27,115.32 A17.H2
N_AC03  (via drill 0.61)
  Top 0.305: v90.42,68.58 v110.74,88.9
  15 0.305: v90.42,68.58 101.85,57.15 101.85,51.82 108.2,45.47 108.2,39.12 109.22,38.1 109.22,34.04 B16.M2
  Bottom 0.305: v110.74,88.9 110.74,89.66 112.27,91.19 104.14,99.31 104.14,100.33 98.55,105.92 98.55,107.7 97.28,108.97 A17.K2
N_AC04  (via drill 0.61)
  Top 0.305: v149.1,59.69 149.1,58.17 141.48,50.55 131.06,50.55 120.65,40.13 119.38,40.13 109.98,30.73 109.98,27.69 B16.P2
  Bottom 0.305: v149.1,59.69 149.1,59.94 144.27,64.77 143.51,64.77 141.73,66.55 134.62,66.55 129.03,72.14 127,72.14 124.21,74.93 123.19,74.93 98.55,99.57 98.55,101.35 97.28,102.62 A17.M2
N_AC05  (via drill 0.61)
  Top 0.305: v92.2,62.74 92.2,62.99 v104.9,75.69
  15 0.305: v92.2,62.74 92.2,48.77 93.98,46.99 93.98,45.47 108.2,31.24 108.2,26.42 109.22,25.4 109.22,21.34 B16.S2
  Bottom 0.305: v104.9,75.69 104.9,86.87 98.55,93.22 98.55,95 97.28,96.27 A17.P2
N_AC06  (via drill 0.61)
  Top 0.305: v83.82,68.33 80.77,71.37 92.71,83.31 92.71,84.33 95,86.61 95,88.65 A17.S2
  Bottom 0.305: v83.82,68.33 96.52,55.63 96.52,53.09 B17.E2
N_AC07  (via drill 0.61)
  Top 0.305: v114.3,62.23 114.05,61.98 114.05,61.21 99.31,46.48 97.54,46.48 B17.H2
  15 0.305: v114.3,62.23 114.3,64.77 95.5,83.57 95.5,85.09 93.98,86.61 A17.T2
N_AC08  (via drill 0.61)
  Top 0.305: v95,45.97 91.19,49.78 v107.19,65.79
  Bottom 0.305: v95,45.97 96.52,44.45 96.52,40.39 B17.K2 | v107.19,65.79 102.11,70.87 102.11,72.14 93.98,80.26 A17.V2
N_AC09
  15 0.305: B17.M2 96.27,33.78 94.49,33.78 79.5,48.77 79.5,72.64 78.23,73.91 78.23,75.44 73.15,80.52 73.15,108.2 86.61,121.67 84.58,123.7 82.8,123.7 81.53,124.97 A18.D2
N_AC10
  15 0.305: B17.P2 96.52,27.69 96.52,30.73 78.74,48.51 78.74,49.53 76.45,51.82 76.45,55.63 75.18,56.9 75.18,59.44 73.15,61.47 73.15,66.29 71.88,67.56 71.88,80.77 62.99,89.66 62.99,90.68 60.45,93.22 60.45,96.52 84.58,120.65 83.57,121.67 A18.E2
N_AC11  (via drill 0.61)
  Top 0.305: v122.43,54.1 122.17,53.85 121.67,53.85 98.3,30.48 98.3,26.42 97.28,25.4 97.28,21.34 B17.S2
  Bottom 0.305: v122.43,54.1 122.43,55.63 120.14,57.91 120.14,58.93 95.5,83.57 95.5,87.38 92.96,89.92 92.96,91.44 91.44,92.96 91.44,93.98 89.15,96.27 89.15,101.6 85.09,105.66 85.09,106.68 82.8,108.97 82.8,114.55 A18.H2
N_ACCEPT
  Bottom 0.305: A20.S2 59.44,90.17 61.98,90.17 78.74,73.41 84.07,73.41 88.9,78.23 92.96,78.23 101.35,69.85 101.6,69.85 106.68,64.77 107.95,64.77 115.32,57.4 116.84,57.4 118.36,55.88 B15.D2
N_ACCLR  (via drill 0.61)
  Top 0.305: v107.95,68.07 106.17,66.29 106.17,66.04 84.58,44.45 84.58,40.39 B18.K2
  Bottom 0.305: v107.95,68.07 107.95,70.1 94.74,83.31 94.74,84.33 85.85,93.22 85.85,95 84.58,96.27 A18.P2
N_ADD00
  15 0.305: B20.E2 58.42,53.09 58.42,57.15 57.4,58.17 57.4,70.61 55.63,72.39 55.63,78.99 54.1,80.52 54.1,109.22 68.83,123.95 68.07,124.71 A19.D2
N_ADD01  (via drill 0.61)
  Top 0.305: v38.1,62.99 38.1,66.8 39.88,68.58 39.88,74.93 57.66,92.71 57.66,93.73 60.2,96.27 60.2,101.6 60.96,102.36 60.96,103.38 63.25,105.66 63.25,112.01 69.6,118.36 69.6,120.4 A19.E2
  Bottom 0.305: v38.1,62.99 54.61,46.48 58.17,46.48 B20.H2
N_ADD02  (via drill 0.61)
  Top 0.305: v52.07,42.67 45.21,49.53 47.5,51.82 47.5,56.13 55.37,64.01 55.37,65.02 70.36,80.01 70.36,81.03 79.25,89.92 v79.25,91.44
  Bottom 0.305: v52.07,42.67 54.61,40.13 58.17,40.13 B20.K2 | v79.25,91.44 79.25,92.46 72.39,99.31 72.39,100.33 70.1,102.62 70.1,114.55 A19.H2
N_ADD03  (via drill 0.61)
  Top 0.305: v35.05,58.93 35.56,58.93 41.15,64.52 41.15,75.18 58.42,92.46 58.42,93.47 60.96,96.01 60.96,97.03 69.6,105.66 69.6,107.7 A19.K2
  Bottom 0.305: v35.05,58.93 35.05,55.12 55.63,34.54 56.64,34.54 57.4,33.78 58.17,33.78 B20.M2
N_ADD04  (via drill 0.61)
  Top 0.305: v47.5,38.1 52.83,38.1 72.9,58.17 72.9,65.02 77.47,69.6 77.47,72.64 v79.25,74.42
  Bottom 0.305: v47.5,38.1 47.75,37.85 47.75,36.07 55.63,28.19 56.64,28.19 57.4,27.43 58.17,27.43 B20.P2 | v79.25,74.42 79.25,89.92 81.03,91.69 73.15,99.57 73.15,101.35 71.88,102.62 A19.M2
N_ADD05  (via drill 0.61)
  Top 0.305: v82.3,50.8 82.3,48.51 59.18,25.4 59.18,21.34 B20.S2
  15 0.305: v82.3,50.8 82.3,73.66 v78.23,77.72
  Bottom 0.305: v78.23,77.72 78.23,81.79 76.45,83.57 76.45,89.92 73.15,93.22 73.15,95 71.88,96.27 A19.P2
N_ADD06
  Top 0.305: B21.E2 46.48,53.09 46.48,56.13 54.61,64.26 54.61,65.28 69.6,80.26 69.6,85.6 70.36,86.36 70.36,89.41 A19.S2
N_ADD07  (via drill 0.61)
  Top 0.305: v38.1,56.64 36.83,57.91 45.47,66.55 45.97,66.55 49.28,69.85 52.07,69.85 56.13,73.91 56.9,73.91 66.55,83.57 66.55,85.34 67.82,86.61 A19.T2
  Bottom 0.305: v38.1,56.64 45.72,49.02 45.72,46.74 B21.H2
N_ADD08
  Top 0.305: B21.K2 45.72,40.39 45.72,44.2 39.62,50.29 53.85,64.52 53.85,66.29 67.82,80.26 A19.V2
N_ADD09
  2 0.305: B21.M2 45.72,34.04 45.72,38.1 34.54,49.28 57.66,72.39 57.66,81.03 60.2,83.57 60.2,118.87 54.86,124.21 55.37,124.71 A20.D2
N_ADD10  (via drill 0.61)
  Top 0.305: v16,66.29 16,89.15 32.26,105.41 32.26,106.43 34.8,108.97 34.8,113.03 45.47,123.7 49.02,123.7 55.63,117.09 56.9,118.36 56.9,119.38 59.18,121.67 A20.E2
  Bottom 0.305: v16,66.29 16,61.47 18.54,58.93 18.54,57.91 27.18,49.28 27.18,48.26 32,43.43 32,39.12 42.93,28.19 43.94,28.19 44.7,27.43 45.47,27.43 B21.P2
N_ADD11  (via drill 0.61)
  Top 0.305: v25.4,43.18 25.4,56.9 23.11,59.18 56.9,92.96 56.9,98.3 57.66,99.06 57.66,100.08 60.2,102.62 60.2,114.3 59.18,115.32 A20.H2
  Bottom 0.305: v25.4,43.18 25.65,42.93 25.65,39.12 27.94,36.83 27.94,35.81 42.67,21.08 45.47,21.08 B21.S2
N_BAC00  (via drill 0.61)
  2 0.305: v189.74,67.82 189.48,67.56 188.21,67.56 187.2,66.55 187.2,64.52 182.37,59.69 182.37,56.13 B10.D2
  15 0.305: v189.74,67.82 189.74,76.71 170.43,96.01 170.43,97.54 165.35,102.62 165.35,104.39 v164.85,104.9
  Bottom 0.305: v164.85,104.9 164.85,106.93 148.08,123.7 146.3,123.7 145.03,124.97 A13.D2
N_BAC01  (via drill 0.61)
  2 0.305: v197.36,78.74 197.36,75.95 195.83,74.42 195.83,71.88 183.13,59.18 183.13,57.15 184.4,55.88 v184.15,55.63
  15 0.305: v197.36,78.74 196.6,79.5 196.6,81.53 166.88,111.25 163.07,111.25 158.75,115.57 156.72,115.57 150.37,121.92 148.34,121.92 A13.E2
  Bottom 0.305: v184.15,55.63 184.15,41.66 185.42,40.39 B10.K2
N_BAC02  (via drill 0.61)
  Top 0.305: v175.77,83.31 175.77,82.55 174.75,81.53 174.75,79.5 172.72,77.47 170.69,77.47 159,65.79 159,61.72 151.38,54.1 150.88,54.1 v149.86,53.09
  Bottom 0.305: v175.77,83.31 163.83,95.25 163.83,97.54 148.08,113.28 148.08,115.32 A13.H2 | v149.86,53.09 150.37,53.09 169.16,34.29 170.18,34.29 182.12,22.35 183.9,22.35 185.17,21.08 B10.S2
N_BAC03  (via drill 0.61)
  Top 0.305: v166.62,87.38 166.62,87.12 159,79.5 159,78.99 v153.42,73.41
  Bottom 0.305: v166.62,87.38 148.08,105.92 148.08,108.97 A13.K2 | v153.42,73.41 153.92,73.41 168.15,59.18 168.15,57.4 169.42,56.13 B11.D2
N_BAC04  (via drill 0.61)
  Top 0.305: v177.55,48.26 173.48,44.2 173.48,40.39 B11.K2 | v161.29,77.47 161.29,80.77 166.12,85.6 166.62,85.6 v166.88,85.85
  Bottom 0.305: v177.55,48.26 177.55,52.32 168.4,61.47 168.4,68.07 165.61,70.87 165.61,73.15 v161.29,77.47 | v166.88,85.85 166.62,85.85 164.85,87.63 164.85,87.88 151.38,101.35 149.86,101.35 148.34,102.87 A13.M2
N_BAC05  (via drill 0.61)
  Top 0.305: v124.46,71.88 124.71,71.88 145.8,92.96 145.8,95 A13.P2
  Bottom 0.305: v124.46,71.88 137.92,58.42 138.43,58.42 145.03,51.82 145.03,51.31 172.72,23.62 172.72,21.34 B11.S2
N_BAC06  (via drill 0.61)
  Top 0.305: v139.95,77.22 139.95,80.26 144.27,84.58 144.27,85.09 145.8,86.61 145.8,88.65 A13.S2
  Bottom 0.305: v139.95,77.22 156.72,60.45 156.72,56.13 B12.D2
N_BAC07  (via drill 0.61)
  Top 0.305: v171.7,53.34 160.78,42.42 160.78,40.39 B12.K2 | v143.26,85.09 143.26,85.85 144.02,86.61 A13.T2
  Bottom 0.305: v171.7,53.34 171.7,56.64 v143.26,85.09
N_BAC08  (via drill 0.61)
  Top 0.305: v134.11,70.1 134.37,70.1 144.53,80.26 A13.V2
  15 0.305: v134.11,70.1 146.3,57.91 146.3,51.82 149.35,48.77 149.35,42.42 155.7,36.07 155.7,29.72 160.02,25.4 160.02,21.34 B12.S2
N_BAC09  (via drill 0.61)
  Top 0.305: v123.95,116.08 125.48,117.6 125.98,117.6 126.75,118.36 126.75,118.87 128.78,120.9 129.29,120.9 131.32,122.94 131.32,124.71 A14.D2
  15 0.305: v123.95,116.08 123.95,105.66 126.75,102.87 127,102.87 128.02,101.85 128.02,99.31 130.05,97.28 130.05,79.25 130.81,78.49 130.81,71.12 142.75,59.18 142.75,57.4 144.02,56.13 B13.D2
N_BAC10  (via drill 0.61)
  15 0.305: v120.9,120.4 120.9,104.14 112.52,95.76 130.05,78.23 130.05,59.18 145.8,43.43 145.8,41.91 147.32,40.39 B13.K2
  Bottom 0.305: v120.9,120.4 125.98,120.4 127,119.38 127.76,119.38 130.05,121.67 134.37,121.67 A14.E2
N_BAC11  (via drill 0.61)
  Top 0.305: v109.73,77.22 109.73,80.01 124.71,95 128.78,95 139.45,105.66 139.45,108.2 v139.7,108.46
  Bottom 0.305: v109.73,77.22 112.01,74.93 112.01,71.12 120.9,62.23 120.9,58.17 133.6,45.47 133.6,39.12 134.62,38.1 134.62,36.58 147.32,23.88 147.32,21.34 B13.S2 | v139.7,108.46 139.7,109.22 136.65,112.27 136.65,114.05 135.38,115.32 A14.H2
N_BREAK  (via drill 0.61)
  15 0.305: v75.44,89.41 76.45,89.41 90.93,74.93 90.93,72.9 98.3,65.53 98.3,61.72 102.62,57.4 102.62,55.88 v111,47.5
  Bottom 0.305: v75.44,89.41 69.34,95.5 64.52,95.5 63.5,96.52 59.44,96.52 A20.P2 | v111,47.5 111,46.48 133.1,24.38 133.1,22.86 134.62,21.34 B14.S2
N_BRKRQ
  15 0.305: B18.P2 83.82,27.69 83.82,31.75 79.5,36.07 79.5,46.48 77.47,48.51 77.47,49.78 72.39,54.86 72.39,55.88 66.8,61.47 66.8,70.61 65.02,72.39 65.02,82.3 63.75,83.57 63.75,87.88 61.72,89.92 61.72,90.93 59.69,92.96 59.69,93.98 57.4,96.27 57.4,108.2 A20.K2
N_CAINCR
  Bottom 0.305: B19.K2 71.12,40.39 71.12,43.43 69.34,45.21 69.34,46.23 66.8,48.77 66.8,59.18 52.83,73.15 52.83,75.44 32,96.27 32,101.85 A22.M2
N_DATA00  (via drill 0.61)
  Top 0.305: v22.35,98.04 22.35,106.93 39.12,123.7 40.89,123.7 42.16,124.97 A21.D2
  Bottom 0.305: v22.35,98.04 22.35,80.52 23.37,79.5 23.37,66.29 33.02,56.64 33.02,53.09 B22.E2
N_DATA01  (via drill 0.61)
  Top 0.305: v22.35,72.64 22.35,82.8 32.26,92.71 32.26,93.73 34.8,96.27 34.8,101.6 44.96,111.76 44.96,112.78 47.5,115.32 47.5,120.65 46.48,121.67 A21.E2
  Bottom 0.305: v22.35,72.64 22.61,72.39 22.61,66.04 28.7,59.94 28.7,48.77 30.99,46.48 32.77,46.48 B22.H2
N_DATA02  (via drill 0.61)
  Top 0.305: v19.3,69.6 19.3,80.77 31.5,92.96 31.5,99.31 44.2,112.01 44.2,114.05 A21.H2
  Bottom 0.305: v19.3,69.6 19.3,58.17 27.94,49.53 27.94,48.51 33.02,43.43 33.02,40.39 B22.K2
N_DATA03  (via drill 0.61)
  Top 0.305: v16,54.36 16,63.75 44.96,92.71 44.96,93.73 47.5,96.27 47.5,107.95 46.48,108.97 A21.K2
  Bottom 0.305: v16,54.36 28.7,41.66 28.7,36.07 30.99,33.78 32.77,33.78 B22.M2
N_DATA04  (via drill 0.61)
  Top 0.305: v21.59,41.15 10.16,52.58 12.45,54.86 12.45,61.21 44.2,92.96 44.2,101.35 A21.M2
  Bottom 0.305: v21.59,41.15 33.02,29.72 33.02,27.69 B22.P2
N_DATA05
  2 0.305: B22.S2 33.02,21.34 33.02,25.4 4.83,53.59 44.2,92.96 44.2,95 A21.P2
N_DATA06
  Top 0.305: B23.E2 21.08,53.09 21.08,57.15 22.1,58.17 22.1,62.99 25.4,66.29 25.4,67.82 44.2,86.61 44.2,88.65 A21.S2
N_DATA07
  Top 0.305: B23.H2 20.32,46.74 20.32,50.8 17.53,53.59 18.8,54.86 18.8,65.28 39.12,85.6 40.89,85.6 42.16,86.87 A21.T2
N_DATA08
  15 0.305: B23.K2 20.57,40.39 20.57,42.42 42.67,64.52 42.67,68.33 41.15,69.85 41.15,78.99 42.42,80.26 A21.V2
N_DATA09
  Top 0.305: B23.M2 20.07,32.77 20.07,30.73 18.03,28.7 16.26,28.7 1.02,43.94 1.02,94.23 28.45,121.67 28.45,123.44 29.72,124.71 A22.D2
N_DATA10
  Bottom 0.305: B23.P2 20.32,27.69 20.32,31.75 16,36.07 16,48.77 12.95,51.82 12.95,63.5 12.19,64.26 12.19,77.98 9.65,80.52 9.65,114.55 24.38,129.29 29.72,123.95 31.5,123.95 32.77,122.68 A22.E2
N_DATA11  (via drill 0.61)
  Top 0.305: v6.6,56.9 6.6,80.77 31.5,105.66 31.5,114.05 A22.H2
  Bottom 0.305: v6.6,56.9 12.95,50.55 12.95,39.12 15.24,36.83 15.24,35.81 16,35.05 16,23.37 18.29,21.08 20.07,21.08 B23.S2
N_DATAIN  (via drill 0.61)
  Top 0.305: v35.05,72.64 35.05,76.45 44.96,86.36 44.96,87.38 56.9,99.31 56.9,101.35 A20.M2
  Bottom 0.305: v35.05,72.64 35.05,61.47 55.37,41.15 59.18,41.15 64.52,35.81 65.53,35.81 77.98,23.37 78.49,23.37 80.77,21.08 83.57,21.08 B18.S2
N_EXTA0
  15 0.305: B19.S2 71.12,21.34 71.12,25.4 70.1,26.42 70.1,36.83 50.8,56.13 50.8,57.4 46.99,61.21 46.99,62.23 44.7,64.52 44.7,89.92 22.35,112.27 22.35,114.05 21.08,115.32 A23.H2
N_EXTA1  (via drill 0.61)
  Top 0.305: v84.84,50.55 83.06,48.77 83.06,48.26 72.9,38.1 72.9,32.77 71.88,31.75 71.88,27.69 B19.P2
  Bottom 0.305: v84.84,50.55 86.61,52.32 85.09,53.85 85.09,55.88 82.8,58.17 82.8,61.98 62.48,82.3 58.67,82.3 22.35,118.62 22.35,120.4 21.08,121.67 A23.E2
N_EXTA2
  15 0.305: B19.M2 71.12,34.04 71.12,37.08 51.56,56.64 51.56,57.66 51.05,58.17 51.05,77.22 47.75,80.52 47.75,93.22 19.3,121.67 19.3,123.19 17.78,124.71 A23.D2
N_INIT
  15 0.305: A14.V2 132.33,80.52 133.86,80.52 142.49,71.88 142.49,68.33 175.77,35.05 182.12,35.05 194.82,22.35 196.6,22.35 197.87,21.08 B09.S2
N_IOP1  (via drill 0.61)
  Top 0.305: v190.75,49.53 192.28,51.05 192.79,51.05 193.55,51.82 196.6,51.82 197.1,52.32 197.1,53.09 201.68,57.66 202.95,56.39 202.95,55.12 203.96,54.1 204.98,54.1 205.99,55.12 207.26,55.12 B08.D2
  15 0.305: v190.75,49.53 190.75,50.55 165.1,76.2 165.1,77.47 136.65,105.92 136.65,107.7 135.38,108.97 A14.K2
N_IOP2  (via drill 0.61)
  15 0.305: v160.02,78.99 158.5,80.52 158.5,81.53 144.53,95.5 140.72,95.5 135.38,100.84 135.38,102.62 A14.M2
  Bottom 0.305: v160.02,78.99 161.29,78.99 168.4,71.88 171.96,71.88 173.23,70.61 173.74,70.61 177.8,66.55 181.36,66.55 188.21,59.69 189.23,59.69 194.82,54.1 198.63,54.1 209.3,43.43 209.3,41.91 210.82,40.39 B08.K2
N_IOP4  (via drill 0.61)
  Top 0.305: v209.3,14.22 209.3,18.8 B08.S2
  15 0.305: v209.3,14.22 136.4,87.12 136.4,90.93 135.38,91.95 135.38,96.27 A14.P2
N_IRQ  (via drill 0.61)
  Top 0.305: v60.2,80.52 60.2,82.3 70.61,92.71 71.63,92.71 73.91,95 77.98,95 82.3,99.31 82.3,101.35 A18.M2
  Bottom 0.305: v60.2,80.52 71.88,68.83 71.88,67.56 77.47,61.98 77.47,61.47 82.8,56.13 82.8,51.82 83.82,50.8 83.82,46.74 B18.H2
N_LINE  (via drill 0.61)
  Top 0.305: v76.2,57.4 74.17,59.44 75.95,61.21 75.95,67.06 78.23,69.34 78.23,71.88 v83.57,77.22
  Bottom 0.305: v76.2,57.4 79.5,54.1 79.5,42.42 83.82,38.1 83.82,34.04 B18.M2 | v83.57,77.22 83.57,77.98 81.28,80.26 A18.V2
N_MB00
  15 0.305: A15.D2 119.63,125.98 123.95,125.98 141.48,143.51 191.52,143.51 195.83,139.19 198.37,139.19 198.63,138.94 200.91,138.94 201.17,138.68 205.49,138.68 216.92,127.25 218.44,127.25 219.96,125.73 A07.D2
N_MB01  (via drill 0.61)
  Top 0.305: v145.54,136.4 134.37,136.4 122.68,124.71 122.68,122.94 A15.E2
  15 0.305: v145.54,136.4 181.36,136.4 184.91,132.84 185.93,132.84 188.47,130.3 194.82,130.3 207.52,117.6 210.82,117.6 212.09,118.87 212.6,118.87 213.36,118.11 213.36,116.59 215.14,114.81 216.66,114.81 220.22,111.25 222,111.25 223.27,109.98 A07.K2
N_MB02  (via drill 0.61)
  15 0.305: v114.55,119.38 114.81,119.13 120.14,124.46 122.94,124.46 123.7,123.7 160.78,123.7 164.08,120.4 183.13,120.4 186.18,117.35 192.53,117.35 205.23,104.65 211.58,104.65 212.85,103.38 214.88,103.38 217.93,100.33 218.44,100.33 223.52,95.25 223.52,91.19 A07.S2
  Bottom 0.305: v114.55,119.38 116.84,119.38 118.62,117.6 120.4,117.6 121.67,116.33 A15.H2
N_MB03  (via drill 0.61)
  Top 0.305: v134.87,107.7 134.87,107.44 132.08,104.65 128.02,104.65 127,103.63 122.94,103.63 A15.M2
  2 0.305: v177.8,78.74 178.31,78.74 207.26,107.7 209.3,107.7 A08.K2
  Bottom 0.305: v134.87,107.7 147.07,95.5 149.61,95.5 149.86,95.25 152.65,95.25 156.46,91.44 157.48,91.44 169.42,79.5 177.04,79.5 v177.8,78.74
N_MB03\  (via drill 0.61)
  Top 0.305: v178.56,142.24 177.55,141.22 171.96,141.22 171.45,140.72 169.42,140.72 169.16,140.46 156.21,140.46 133.1,117.35 128.02,117.35 122.68,112.01 122.68,110.24 A15.K2
  15 0.305: v178.56,142.24 191.77,142.24 196.09,137.92 199.9,137.92 201.93,135.89 201.93,133.35 206.25,129.03 206.25,127.25 207.52,125.98 A08.D2
N_MB04  (via drill 0.61)
  Top 0.305: v131.06,85.6 133.35,85.6 147.57,99.82 147.83,99.82 148.34,100.33 148.34,100.84 168.91,121.41 168.91,121.92 169.93,122.94 169.93,123.44 v184.66,138.18
  Bottom 0.305: v131.06,85.6 126.49,90.17 122.94,90.17 A15.S2 | v184.66,138.18 184.66,137.92 193.55,129.03 193.55,127.25 194.82,125.98 A09.D2
N_MB04\  (via drill 0.61)
  Top 0.305: v186.94,114.3 186.18,114.3 v179.83,107.95 | v161.8,120.9 158.5,120.9 157.99,120.4 156.46,120.4 155.7,119.63 155.7,114.81 v131.32,90.42
  Bottom 0.305: v186.94,114.3 187.45,113.79 187.45,112.27 208.79,90.93 210.57,90.93 A08.S2 | v179.83,107.95 176.53,107.95 164.08,120.4 162.31,120.4 v161.8,120.9 | v131.32,90.42 130.56,90.42 125.98,95 124.46,95 122.94,96.52 A15.P2
N_MB05  (via drill 0.61)
  2 0.305: v137.41,75.44 152.15,75.44 153.67,76.96 154.43,76.96 155.45,77.98 157.48,77.98 159.51,80.01 160.53,80.01 162.81,82.3 167.39,82.3 v186.44,101.35
  Bottom 0.305: v137.41,75.44 137.16,75.69 126.75,75.69 121.92,80.52 119.63,80.52 A15.V2 | v186.44,101.35 189.48,101.35 196.6,94.23 196.6,92.71 198.12,91.19 A09.S2
N_MB05\  (via drill 0.61)
  2 0.305: v134.11,76.71 135.64,75.18 136.91,76.45 137.67,76.45 139.45,78.23 152.4,78.23 162.81,88.65 169.16,88.65 185.17,104.65 191.52,104.65 194.56,107.7 196.6,107.7 A09.K2
  Bottom 0.305: v134.11,76.71 129.29,81.53 126.75,81.53 121.41,86.87 119.63,86.87 A15.T2
N_MB06  (via drill 0.61)
  Top 0.305: v149.1,137.41 133.1,137.41 129.29,133.6 122.94,133.6 113.28,123.95 111.51,123.95 110.24,122.68 A16.E2
  Bottom 0.305: v149.1,137.41 149.35,137.16 157.23,137.16 157.99,136.4 160.78,136.4 185.42,111.76 185.42,110.24 A10.K2
N_MB06\  (via drill 0.61)
  Top 0.305: v131.57,138.43 129.54,136.4 121.67,136.4 111.25,125.98 106.93,125.98 A16.D2 | v176.78,121.92 177.04,121.92 178.82,123.7 180.59,123.7 181.86,124.97 A10.D2
  Bottom 0.305: v131.57,138.43 160.27,138.43 v176.78,121.92
N_MB07  (via drill 0.61)
  Top 0.305: v142.49,98.55 142.49,100.08 147.07,104.65 151.13,104.65 168.15,121.67 168.15,122.17 169.16,123.19 169.16,124.46 169.42,124.71 A11.D2
  Bottom 0.305: v142.49,98.55 126.49,114.55 121.67,114.55 120.14,116.08 114.05,109.98 110.24,109.98 A16.K2
N_MB07\
  15 0.305: A10.S2 185.17,90.93 180.85,90.93 164.08,107.7 145.03,107.7 141.73,111 136.65,111 128.27,119.38 127,119.38 122.68,123.7 120.4,123.7 111.51,114.81 110.24,116.08 A16.H2
N_MB08  (via drill 0.61)
  Top 0.305: v150.11,76.71 152.91,79.5 157.73,79.5 165.61,87.38 165.61,87.88 166.62,88.9 167.64,87.88 167.64,87.63 169.42,85.85 170.43,85.85 172.47,87.88 172.47,89.92 A11.S2
  Bottom 0.305: v150.11,76.71 150.11,77.22 145.03,82.3 127,82.3 121.67,87.63 120.65,87.63 113.28,95 111.76,95 110.24,96.52 A16.P2
N_MB08\  (via drill 0.61)
  Top 0.305: v127.76,118.36 113.03,103.63 110.24,103.63 A16.M2 | v162.81,97.03 162.81,97.28 171.2,105.66 171.2,107.7 A11.K2
  Bottom 0.305: v127.76,118.36 130.56,118.36 131.32,117.6 142.24,117.6 v162.81,97.03
N_MB09
  Top 0.305: A16.S2 110.24,90.93 113.28,90.93 115.06,92.71 116.08,92.71 118.36,95 122.68,95 130.56,102.87 131.57,102.87 140.46,111.76 141.48,111.76 153.42,123.7 155.19,123.7 156.46,124.97 A12.D2
N_MB10  (via drill 0.61)
  Top 0.305: v123.7,68.07 123.7,68.58 150.11,95 150.62,95 151.38,95.76 151.38,98.55 152.15,99.31 152.15,103.38 156.46,107.7 158.5,107.7 A12.K2
  Bottom 0.305: v123.7,68.07 106.68,85.09 106.68,86.61 A16.T2
N_MB11  (via drill 0.61)
  Top 0.305: v121.41,67.31 v150.37,96.27
  Bottom 0.305: v121.41,67.31 108.2,80.52 106.93,80.52 A16.V2 | v150.37,96.27 152.65,96.27 156.72,92.2 158.5,92.2 159.77,90.93 A12.S2
N_MBINCR  (via drill 0.61)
